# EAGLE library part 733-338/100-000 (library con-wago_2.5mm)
Serie 733, Stiftleiste (für Leiterplatten) Einpressstift 0,6 x 0,6 mm / Series 733, Male header (for PCBs) Press-in pin 0.6 x 0.6 mm Polzahl / Pole No.: 8 Rastermaß / Pitch: 2.5 mm Bemessungsspannung / Rated Voltage: 160 V Nennstrom / Nominal Current: 4 A Farbe / Color: lichtgrau / light gray Stand: 01.01.2012. Die jeweils aktuellen Daten zu diesem Artikel finden Sie in unserem Produktkatalog, den Sie unter www.wago.com einsehen können. As of: 01/01/2012. Please find the newest data for this article in our product catalogue, which can be viewed under www.wago.com.

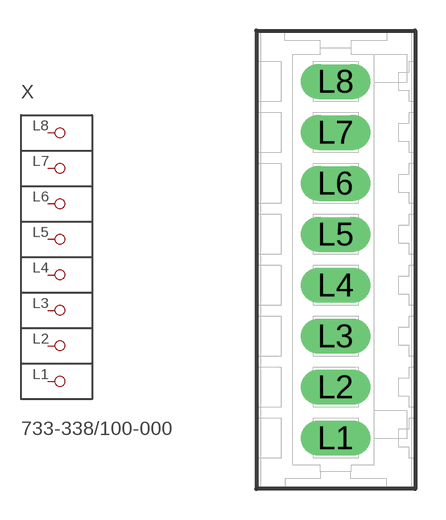
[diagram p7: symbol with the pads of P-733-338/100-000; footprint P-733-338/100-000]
Designator prefix X

## 733-338/100-000  [P-733-338/100-000]
L1  P1
L2  P2
L3  P3
L4  P4
L5  P5
L6  P6
L7  P7
L8  P8

## Footprint P-733-338/100-000 (pad centres in mm)
drill 1.15 long: L1 0,-8.75; L2 0,-6.25; L3 0,-3.75; L4 0,-1.25; L5 0,1.25; L6 0,3.75; L7 0,6.25; L8 0,8.75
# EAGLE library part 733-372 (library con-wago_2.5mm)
Serie 733, Stiftleiste (für Leiterplatten) Einlötstift abgewinkelt 0,8 x 0,8 mm / Series 733, Male header (for PCBs) Angled solder pin 0.8 x 0.8 mm Polzahl / Pole No.: 12 Rastermaß / Pitch: 2.5 mm Bemessungsspannung / Rated Voltage: 160 V Nennstrom / Nominal Current: 6 A Lötstiftlänge: / Solder Pin Length: 3.7 mm Farbe / Color: lichtgrau / light gray Stand: 01.01.2012. Die jeweils aktuellen Daten zu diesem Artikel finden Sie in unserem Produktkatalog, den Sie unter www.wago.com einsehen können. As of: 01/01/2012. Please find the newest data for this article in our product catalogue, which can be viewed under www.wago.com.

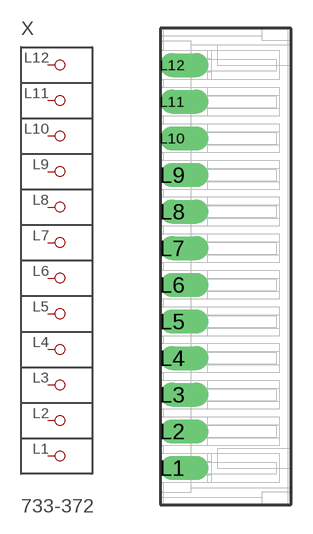
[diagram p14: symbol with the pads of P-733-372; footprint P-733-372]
Designator prefix X

## 733-372  [P-733-372]
L1  P1
L2  P2
L3  P3
L4  P4
L5  P5
L6  P6
L7  P7
L8  P8
L9  P9
L10  P10
L11  P11
L12  P12

## Footprint P-733-372 (pad centres in mm)
drill 1.1 pad 1.6 offset: L1 -3.65,-13.75; L2 -3.65,-11.25; L3 -3.65,-8.75; L4 -3.65,-6.25; L5 -3.65,-3.75; L6 -3.65,-1.25; L7 -3.65,1.25; L8 -3.65,3.75; L9 -3.65,6.25; L10 -3.65,8.75; L11 -3.65,11.25; L12 -3.65,13.75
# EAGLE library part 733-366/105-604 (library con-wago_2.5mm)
Serie 733, Stiftleiste (für Leiterplatten) Einlötstift abgewinkelt 0,8 x 0,8 mm / Series 733, Male header (for PCBs) Angled solder pin 0.8 x 0.8 mm Polzahl / Pole No.: 6 Rastermaß / Pitch: 2.5 mm Bemessungsspannung / Rated Voltage: 160 V Nennstrom / Nominal Current: 6 A Lötstiftlänge: / Solder Pin Length: 2.4 mm Farbe / Color: schwarz / black Stand: 01.01.2012. Die jeweils aktuellen Daten zu diesem Artikel finden Sie in unserem Produktkatalog, den Sie unter www.wago.com einsehen können. As of: 01/01/2012. Please find the newest data for this article in our product catalogue, which can be viewed under www.wago.com.

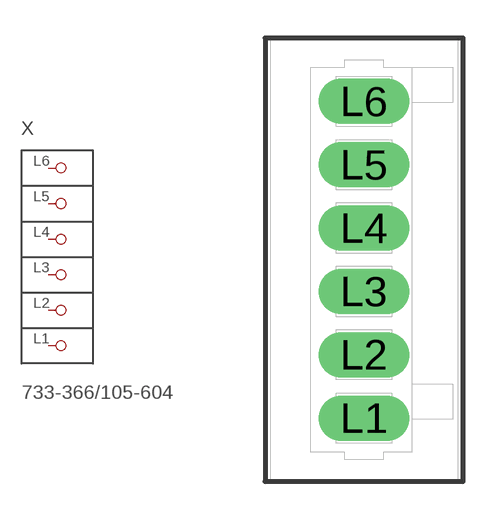
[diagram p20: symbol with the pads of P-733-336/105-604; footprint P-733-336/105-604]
Designator prefix X

## 733-366/105-604  [P-733-336/105-604]
L1  P1
L2  P2
L3  P3
L4  P4
L5  P5
L6  P6

## Footprint P-733-336/105-604 (pad centres in mm)
drill 1.2 long: L1 0,-6.25; L2 0,-3.75; L3 0,-1.25; L4 0,1.25; L5 0,3.75; L6 0,6.25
